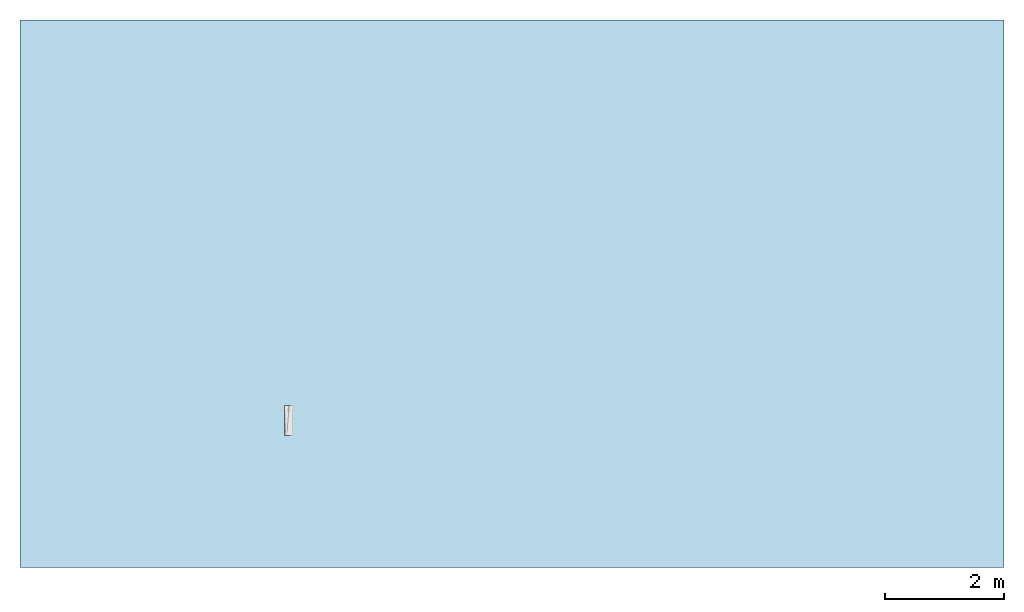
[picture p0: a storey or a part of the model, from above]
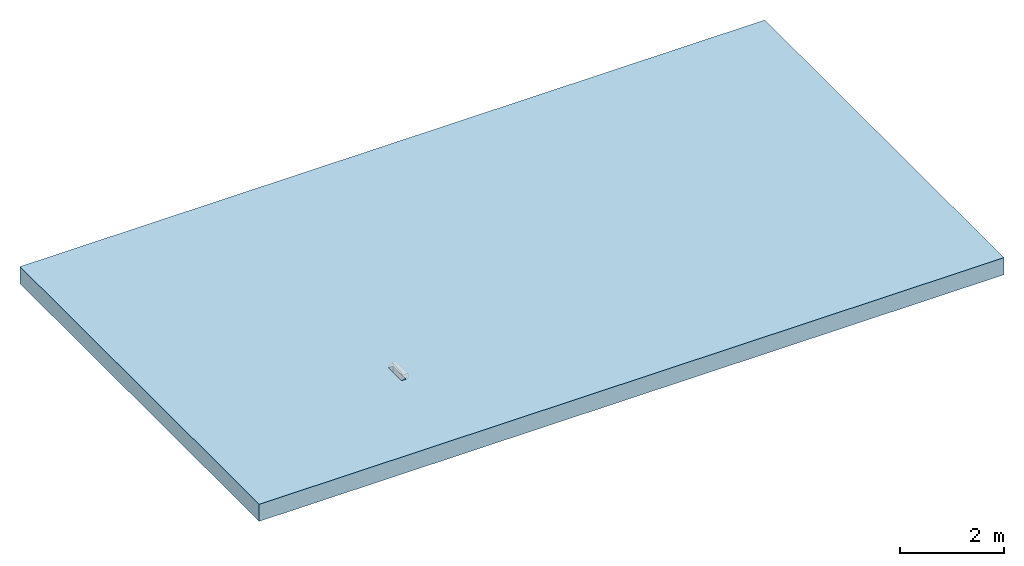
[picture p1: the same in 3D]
Properties of the parts of a building model (IFC2X3)

# File
Description: ViewDefinition [CoordinationView]
File name: 7940 - RH transition kerb - 500mm LG.ifc
Time: 2013-09-02T12:33:28
Written by: Autodesk Revit 2013
Made in: 20120221_2030(x64)

# IfcProject, Project Number
LongName: Project Name; Phase: Project Status

# IfcSite, Default
RefLatitude: 42, 21, 30, 344238; RefLongitude: -71, -3, -35, -194702; RefElevation: 0 mm

# IfcBuilding
Pset_BuildingCommon - NumberOfStoreys: 1
Other - Project Address: ## Street City, State Zip; Project Number: Project Number; Project Issue Date: Issue Date; Client Name: Owner; Project Name: Project Name; Project Status: Project Status

# IfcBuildingStorey, Level 1
LongName: Level 1; Elevation: 0 mm
Constraints - Elevation Base: 0; Elevation: 0 mm
Graphics - Line Weight: 1; Color: 0; Symbol: M_Level Head - Circle: M_Level Head - Circle; Symbol at End 1 Default: no; Line Pattern: Center; Symbol at End 2 Default: yes
Identity Data - Name: Level 1; Structural: no; Building Story: yes
Dimensions - Computation Height: 0 mm

# IfcBuildingElementProxy: 7940 - RH transition kerb - 500mm LG, Civil-Drainage-Channel-ACO-KerbDrain-SP280:7940 - RH transition kerb - 500mm LG:7940 - RH transition kerb - 500mm LG:311063
In: Level 1
Material: ACO Polymer Concrete.
Phasing - Phase Created: New Construction
Dimensions - Volume: 12693165 mm3; Void Width: 150 mm; AccessDepth: 25 mm; Access hole: 100 mm; Void Length: 500 mm; Endcap void: 230.002 mm; Void Depth: -180 mm
Constraints - Moves With Nearby Elements: no; Level: Level: Level 1
Pset_BuildingElementProxyCommon - Reference: 7940 - RH transition kerb - 500mm LG
Identity Data - Maintenance guidelines: http://www.aco.co.uk/download.php?id=120; Address: ACO Business Park, Hitchin Road, Shefford, Bedfordshire, United Kingdom SG17 5TE; Assembly Code: D2040; e-mail Technical: technical@aco.co.uk; Type Comments: ACO KerbDrain SP280 splayed RH transition unit 500mm long; Price: POA - contact ACO; Model: ACO KerbDrain SP280; Product Code: 7940; Telephone: +44 (0)1462 816666; Cost: 0; e-mail Sales: customersupport@aco.co.uk; Model Description: Combined kerb and drainage system; Manufacturer: ACO Technologies plc - ACO Water Management Division; Fax: +44 (0)1462 815895; Assembly Description: Rain Water Drainage; URL: www.aco.co.uk; Installation guidelines: http://www.aco.co.uk/download.php?id=120; OmniClass Title: Rainwater Removal; Product brochure: http://www.aco.co.uk/download.php?id=120; OmniClass Number: 23.70.50.24; Product Page URL: http://www.aco.co.uk/product_detail.php?id=3
Construction - Closing end cap: no; perforated centre stone: no; LH inlet/outlet end cap: no; RH transition unit: yes; RH inlet/outlet end cap: no; SP280 - 1000: no; LH drop kerb: no; Access Unit: no; Centre Stone: no; LH transition unit: no; RH drop kerb: no; SP280-500: no
Data - Product Standard: BS EN 1433:2002, CE marked, Kitemarked; Concrete Surround Volume - Load Class A 15 - D 400 - Grass or Asphalt Pavement: N/A; Product Weight: 24.6 Kg; Load Class: A 15 - D 400; Concrete Surround Volume - Load Class A 15 - D 400 - Concrete Pavement: N/A; Connection Pipe O.D: N/A; Channel C.S.A: 0.02mm²; ACO Hydraulic Design Software: http://www.acodesign.co.uk; Drainage Slot Width: N/A; Hydraulic Performance: http://www.aco.co.uk/download.php?id=120; Product Dimensions: 500mm x 150mm x 305/280mm (LxWxH); Installation - Concrete Grade: Refer to brochure; Drainage Slot Intake area: N/A; Invert Depth: 280/255mm
General - SerialNumber: 0.000000; TagNumber: 0.000000
Materials and Finishes - Access Cover/Frame Colour: N/A; Access Cover/Frame Finish: N/A; End Cap Material: N/A; Channel Material: Vienite® Synthetic Resin Concrete; Connection Pipe Material: N/A; Channel Colour: Grey; End Cap Colour: N/A; Access Cover/Frame Material: N/A; Connection Pipe Material Colour: N/A
Green Building Properties - End Cap Recycled Material Content: N/A; Channel Recyclable: Fully recyclable; Access Cover/Frame Recyclable: N/A; Channel Recycled Material Content: 20% minimum; Access Cover/Frame Recycled Material Content: N/A; End Cap Recyclable: N/A
Other - CreatedBy: www.aco.co.uk; Revision: 1

# IfcOpeningElement: Recess
In: Level 1
Dimensions - Volume: 60574500000 mm3; Thickness: 400 mm; Area: 151470000 mm2; Perimeter: 51360 mm
Constraints - Related to Mass: no; Level: Level: Level 1; Height Offset From Level: 0 mm; Room Bounding: yes
Phasing - Phase Created: New Construction
Structural - Enable Analytical Model: no; Structural: no
Construction - Default Thickness: 400 mm; Function: 0
Graphics - Coarse Scale Fill Color: 0
Materials and Finishes - Structural Material: Plant
Analytical Properties - Absorptance: 0.1; Roughness: 1

# IfcSlab: Floor:Generic Floor - 400mm, Floor:Generic Floor - 400mm:193825
In: Level 1
PredefinedType: FLOOR; Material: Plant 400 mm
Dimensions - Volume: 60574500000 mm3; Thickness: 400 mm; Area: 151470000 mm2; Perimeter: 51360 mm
Constraints - Related to Mass: no; Level: Level: Level 1; Height Offset From Level: 0 mm; Room Bounding: yes
Phasing - Phase Created: New Construction
Structural - Enable Analytical Model: no; Structural: no
Pset_SlabCommon - Reference: Generic Floor - 400mm; IsExternal: no; LoadBearing: yes
Construction - Default Thickness: 400 mm; Function: 0
Graphics - Coarse Scale Fill Color: 0
Materials and Finishes - Structural Material: Plant
Analytical Properties - Absorptance: 0.1; Roughness: 1
